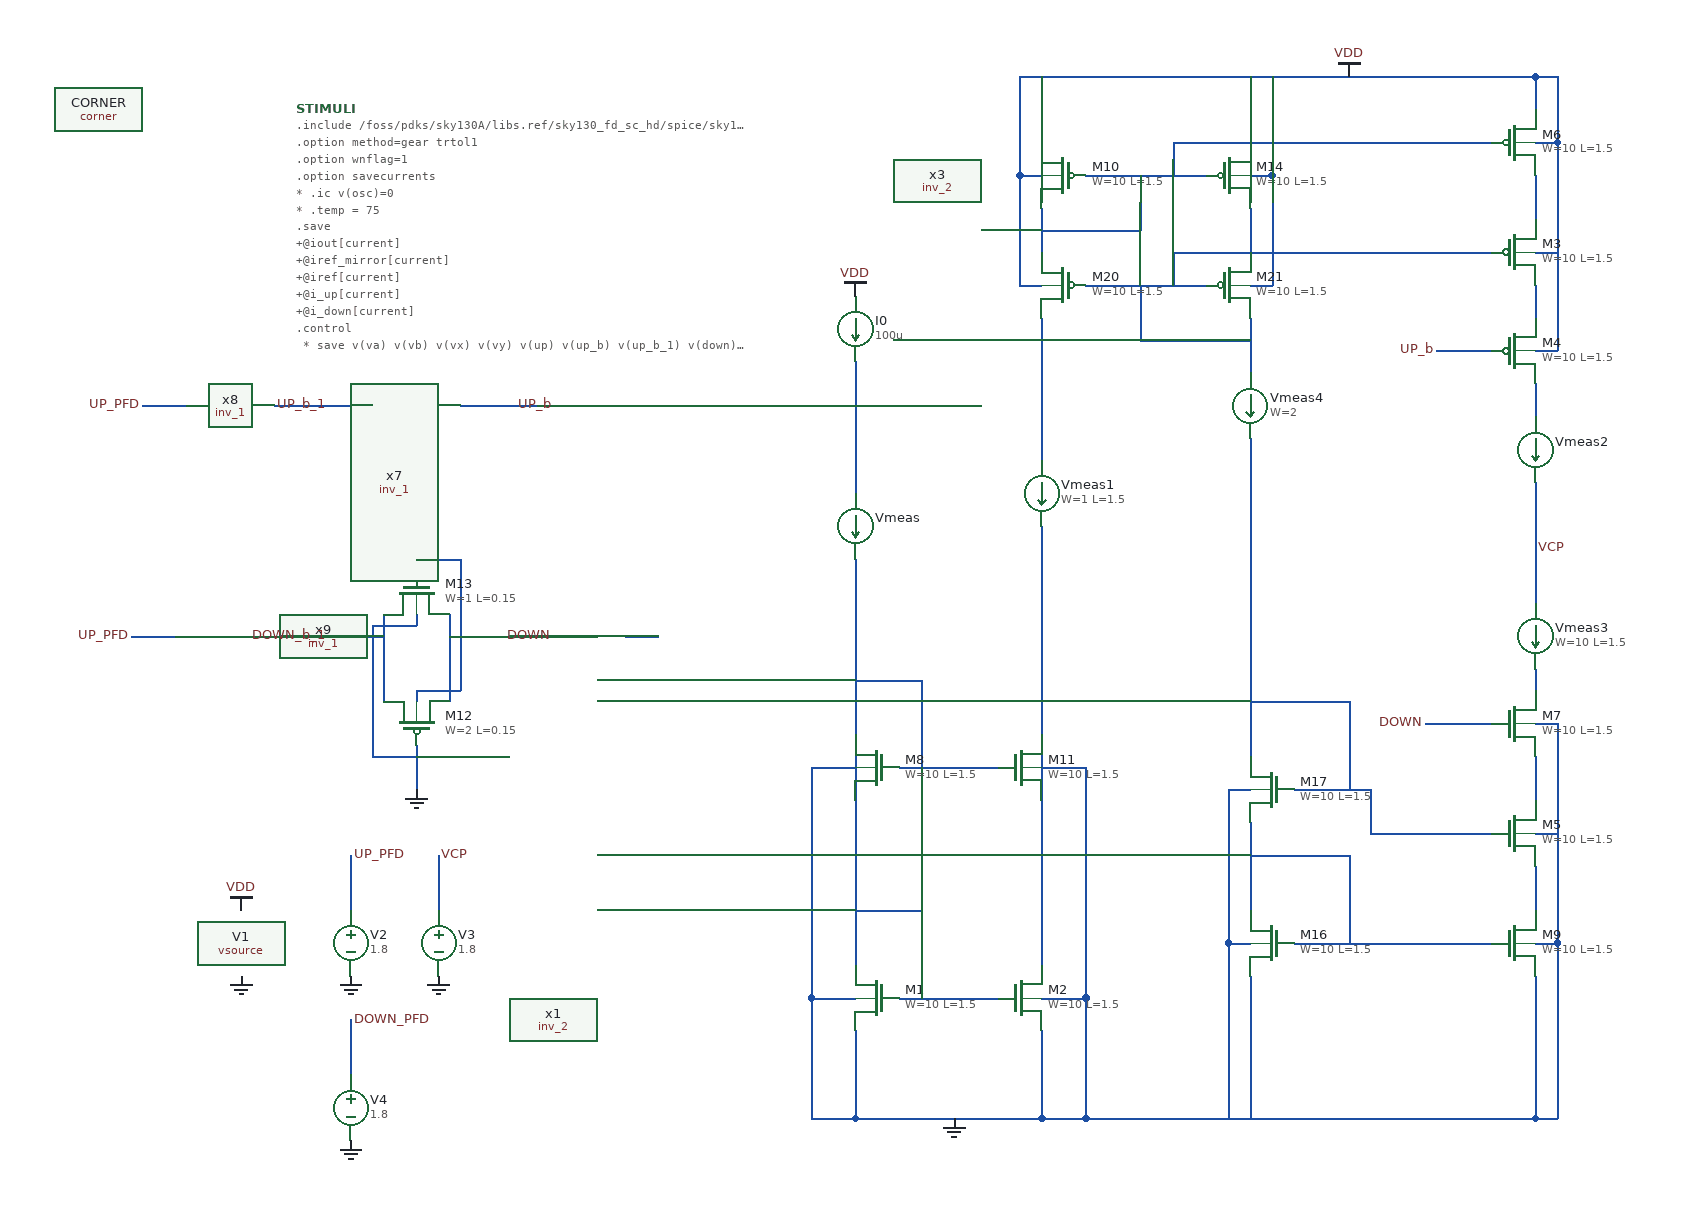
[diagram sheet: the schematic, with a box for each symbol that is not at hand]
v {xschem version=3.4.5 file_version=1.2
}
G {}
K {}
V {}
S {}
E {}
B 2 1530 -1240 2830 -60 {flags=graph
y1=3.6e-120
y2=2e-10
ypos1=0
ypos2=2
divy=5
subdivy=1
unity=1
x1=0
x2=1.8
divx=5
subdivx=1
xlabmag=1.0
ylabmag=1.0


dataset=0
unitx=1
logx=0
logy=0






color="6 5"
node="i(vmeas2)
i(vmeas3)"
linewidth_mult=5}
N 760 -180 850 -180 {
lab=GND}
N 720 -150 720 -70 {
lab=GND}
N 720 -70 890 -70 {
lab=GND}
N 680 -180 720 -180 {
lab=GND}
N 680 -180 680 -70 {
lab=GND}
N 680 -70 720 -70 {
lab=GND}
N 930 -180 930 -70 {
lab=GND}
N 890 -150 890 -70 {
lab=GND}
N 720 -260 780 -260 {
lab=GND}
N 780 -260 780 -180 {
lab=GND}
N 890 -70 930 -70 {
lab=GND}
N 720 -760 720 -710 {
lab=#net1}
N 720 -580 720 -210 {
lab=GND}
N 720 -710 720 -640 {
lab=#net1}
N 1340 -1020 1340 -990 {
lab=VDD}
N 1160 -1020 1340 -1020 {
lab=VDD}
N 1340 -1020 1360 -1020 {
lab=VDD}
N 1360 -1020 1360 -960 {
lab=VDD}
N 1340 -960 1360 -960 {
lab=VDD}
N 930 -70 1240 -70 {
lab=GND}
N 1340 -200 1340 -70 {
lab=GND}
N 1240 -70 1340 -70 {
lab=GND}
N 1340 -230 1360 -230 {
lab=GND}
N 1360 -230 1360 -70 {
lab=GND}
N 1340 -70 1360 -70 {
lab=GND}
N 290 -530 290 -450 {
lab=DOWN_b_1}
N 350 -530 350 -450 {
lab=DOWN}
N 320 -410 320 -370 {
lab=GND}
N 320 -610 320 -570 {
lab=VDD}
N 320 -460 320 -450 {
lab=VDD}
N 320 -460 360 -460 {
lab=VDD}
N 360 -580 360 -460 {
lab=VDD}
N 320 -580 360 -580 {
lab=VDD}
N 320 -530 320 -520 {
lab=GND}
N 280 -520 320 -520 {
lab=GND}
N 280 -520 280 -400 {
lab=GND}
N 280 -400 320 -400 {
lab=GND}
N 190 -720 280 -720 {
lab=UP_b_1}
N 180 -510 290 -510 {
lab=DOWN_b_1}
N 70 -720 110 -720 {
lab=UP_PFD}
N 60 -510 100 -510 {
lab=UP_PFD}
N 260 -310 260 -260 {
lab=UP_PFD}
N 340 -310 340 -260 {
lab=VCP}
N 260 -160 260 -110 {
lab=DOWN_PFD}
N 1340 -400 1340 -360 {
lab=#net2}
N 1340 -300 1340 -260 {
lab=#net3}
N 1340 -830 1340 -800 {
lab=#net4}
N 1340 -930 1340 -880 {
lab=#net5}
N 1340 -770 1360 -770 {
lab=VDD}
N 1360 -960 1360 -770 {
lab=VDD}
N 1340 -860 1360 -860 {
lab=VDD}
N 1340 -430 1360 -430 {
lab=GND}
N 1360 -430 1360 -230 {
lab=GND}
N 1340 -330 1360 -330 {
lab=GND}
N 890 -180 930 -180 {
lab=GND}
N 870 -930 890 -930 {
lab=VDD}
N 870 -1020 870 -930 {
lab=VDD}
N 870 -1020 1160 -1020 {
lab=VDD}
N 930 -930 1040 -930 {
lab=VDD}
N 890 -880 980 -880 {
lab=VDD}
N 980 -930 980 -880 {
lab=VDD}
N 1080 -930 1100 -930 {
lab=VDD}
N 1100 -1020 1100 -930 {
lab=VDD}
N 1060 -230 1080 -230 {
lab=GND}
N 1080 -340 1080 -260 {
lab=#net6}
N 1060 -370 1080 -370 {
lab=GND}
N 1060 -370 1060 -230 {
lab=GND}
N 870 -830 890 -830 {
lab=VDD}
N 930 -830 1040 -830 {
lab=#net7}
N 890 -900 890 -860 {
lab=VDD}
N 1080 -900 1080 -860 {
lab=#net7}
N 980 -830 980 -780 {
lab=#net7}
N 1080 -830 1100 -830 {
lab=VDD}
N 1100 -930 1100 -830 {
lab=VDD}
N 870 -930 870 -830 {
lab=VDD}
N 1250 -770 1300 -770 {
lab=UP_b}
N 1170 -450 1170 -370 {
lab=#net8}
N 1080 -450 1170 -450 {
lab=#net8}
N 1340 -480 1340 -460 {
lab=#net9}
N 1340 -590 1340 -540 {
lab=VCP}
N 1340 -740 1340 -710 {
lab=#net10}
N 890 -610 890 -210 {
lab=GND}
N 890 -800 890 -670 {
lab=#net11}
N 1080 -690 1080 -400 {
lab=#net8}
N 1080 -800 1080 -750 {
lab=#net7}
N 1080 -1020 1080 -960 {
lab=VDD}
N 890 -1020 890 -960 {
lab=VDD}
N 1080 -200 1080 -70 {
lab=GND}
N 1060 -230 1060 -70 {
lab=GND}
N 1170 -310 1170 -230 {
lab=#net6}
N 1080 -310 1170 -310 {
lab=#net6}
N 1120 -230 1300 -230 {
lab=#net6}
N 1120 -370 1190 -370 {
lab=#net8}
N 1190 -370 1190 -330 {
lab=#net8}
N 1190 -330 1300 -330 {
lab=#net8}
N 1340 -650 1340 -590 {
lab=VCP}
N 1010 -960 1300 -960 {
lab=VDD}
N 1010 -960 1010 -930 {
lab=VDD}
N 1010 -860 1300 -860 {
lab=#net7}
N 1010 -860 1010 -830 {
lab=#net7}
N 350 -510 430 -510 {
lab=DOWN}
N 360 -720 430 -720 {
lab=UP_b}
N 510 -720 540 -720 {
lab=#net12}
N 510 -510 540 -510 {
lab=#net13}
N 1240 -430 1300 -430 {
lab=DOWN}
N 760 -390 850 -390 {
lab=GND}
N 680 -390 720 -390 {
lab=GND}
N 720 -470 780 -470 {
lab=GND}
N 780 -470 780 -390 {
lab=GND}
N 890 -390 930 -390 {
lab=GND}
N 930 -390 930 -180 {
lab=GND}
N 680 -390 680 -180 {
lab=GND}
N 980 -780 1080 -780 {
lab=#net7}
C {sky130_fd_pr/nfet_01v8.sym} 740 -180 0 1 {name=M1
L=1.5
W=10
nf=1 
mult=12
ad="'int((nf+1)/2) * W/nf * 0.29'" 
pd="'2*int((nf+1)/2) * (W/nf + 0.29)'"
as="'int((nf+2)/2) * W/nf * 0.29'" 
ps="'2*int((nf+2)/2) * (W/nf + 0.29)'"
nrd="'0.29 / W'" nrs="'0.29 / W'"
sa=0 sb=0 sd=0
model=nfet_01v8
spiceprefix=X
}
C {sky130_fd_pr/nfet_01v8.sym} 870 -180 0 0 {name=M2
L=1.5
W=10
nf=1 
mult=12
ad="'int((nf+1)/2) * W/nf * 0.29'" 
pd="'2*int((nf+1)/2) * (W/nf + 0.29)'"
as="'int((nf+2)/2) * W/nf * 0.29'" 
ps="'2*int((nf+2)/2) * (W/nf + 0.29)'"
nrd="'0.29 / W'" nrs="'0.29 / W'"
sa=0 sb=0 sd=0
model=nfet_01v8
spiceprefix=X
}
C {devices/gnd.sym} 810 -70 0 0 {name=l14 lab=GND}
C {sky130_fd_pr/corner.sym} 30 -990 0 0 {name=CORNER only_toplevel=false corner=tt}
C {devices/code.sym} 210 -991.25 0 0 {name=STIMULI only_toplevel=false value="

.include /foss/pdks/sky130A/libs.ref/sky130_fd_sc_hd/spice/sky130_fd_sc_hd.spice

.option method=gear trtol1
.option wnflag=1
.option savecurrents

* .ic v(osc)=0
* .temp = 75

.save 
+@iout[current]
+@iref_mirror[current]
+@iref[current]
+@i_up[current]
+@i_down[current]


.control
  * save v(va) v(vb) v(vx) v(vy) v(up) v(up_b) v(up_b_1) v(down) v(down_b) v(down_b_1) v(vref) v(vcp)
  save all
  * tran 0.1ns 10us
  dc V3 0 1.8 0.01 V2 0 1.8 1.8 
  remzerovec
  write charge_pump_DC3.raw
  * wrdata /foss/designs/my_design/projects/pll/pfd/xschem_ngspice/charge_pump2_QA.txt v(osc)
  set appendwrite

.endc




"}
C {devices/vsource.sym} 160 -230 0 0 {name=V1 value=1.8 savecurrent=false}
C {devices/gnd.sym} 160 -200 0 0 {name=l2 lab=GND}
C {devices/vdd.sym} 160 -260 0 1 {name=l3 lab=VDD}
C {devices/isource.sym} 720 -790 0 0 {name=I0 value=100u}
C {devices/vdd.sym} 720 -820 0 1 {name=l5 lab=VDD}
C {devices/ammeter.sym} 720 -610 0 0 {name=Vmeas savecurrent=true spice_ignore=0}
C {sky130_fd_pr/pfet_01v8.sym} 1320 -960 0 0 {name=M6
L=1.5
W=10
nf=1
mult=30
ad="'int((nf+1)/2) * W/nf * 0.29'" 
pd="'2*int((nf+1)/2) * (W/nf + 0.29)'"
as="'int((nf+2)/2) * W/nf * 0.29'" 
ps="'2*int((nf+2)/2) * (W/nf + 0.29)'"
nrd="'0.29 / W'" nrs="'0.29 / W'"
sa=0 sb=0 sd=0
model=pfet_01v8
spiceprefix=X
}
C {devices/ammeter.sym} 1340 -680 0 0 {name=Vmeas2 savecurrent=true spice_ignore=0
nf=2}
C {devices/ammeter.sym} 1340 -510 0 0 {name=Vmeas3 savecurrent=true spice_ignore=0
L=1.5
W=10
nf=1
mult=12}
C {sky130_fd_pr/nfet_01v8.sym} 1320 -230 0 0 {name=M9
L=1.5
W=10
nf=1 
mult=12
ad="'int((nf+1)/2) * W/nf * 0.29'" 
pd="'2*int((nf+1)/2) * (W/nf + 0.29)'"
as="'int((nf+2)/2) * W/nf * 0.29'" 
ps="'2*int((nf+2)/2) * (W/nf + 0.29)'"
nrd="'0.29 / W'" nrs="'0.29 / W'"
sa=0 sb=0 sd=0
model=nfet_01v8
spiceprefix=X
}
C {sky130_fd_pr/pfet_01v8.sym} 320 -430 3 0 {name=M12
L=0.15
W=2
nf=2
mult=1
ad="'int((nf+1)/2) * W/nf * 0.29'" 
pd="'2*int((nf+1)/2) * (W/nf + 0.29)'"
as="'int((nf+2)/2) * W/nf * 0.29'" 
ps="'2*int((nf+2)/2) * (W/nf + 0.29)'"
nrd="'0.29 / W'" nrs="'0.29 / W'"
sa=0 sb=0 sd=0
model=pfet_01v8
spiceprefix=X
}
C {sky130_fd_pr/nfet_01v8.sym} 320 -550 1 0 {name=M13
L=0.15
W=1
nf=1 
mult=1
ad="'int((nf+1)/2) * W/nf * 0.29'" 
pd="'2*int((nf+1)/2) * (W/nf + 0.29)'"
as="'int((nf+2)/2) * W/nf * 0.29'" 
ps="'2*int((nf+2)/2) * (W/nf + 0.29)'"
nrd="'0.29 / W'" nrs="'0.29 / W'"
sa=0 sb=0 sd=0
model=nfet_01v8
spiceprefix=X
}
C {devices/vdd.sym} 320 -610 0 0 {name=l11 lab=VDD}
C {devices/gnd.sym} 320 -370 0 0 {name=l12 lab=GND}
C {sky130_stdcells/inv_1.sym} 320 -720 0 0 {name=x7 VGND=GND VNB=GND VPB=VDD VPWR=VDD prefix=sky130_fd_sc_hd__ }
C {sky130_stdcells/inv_1.sym} 150 -720 0 0 {name=x8 VGND=GND VNB=GND VPB=VDD VPWR=VDD prefix=sky130_fd_sc_hd__ }
C {sky130_stdcells/inv_1.sym} 140 -510 0 0 {name=x9 VGND=GND VNB=GND VPB=VDD VPWR=VDD prefix=sky130_fd_sc_hd__ }
C {devices/lab_wire.sym} 70 -720 0 0 {name=p2 sig_type=std_logic lab=UP_PFD}
C {devices/lab_wire.sym} 240 -720 0 0 {name=p15 sig_type=std_logic lab=UP_b_1}
C {devices/lab_wire.sym} 240 -510 2 1 {name=p16 sig_type=std_logic lab=DOWN_b_1}
C {devices/vsource.sym} 260 -230 0 0 {name=V2 value=1.8 savecurrent=false
* "pwl()"}
C {devices/gnd.sym} 260 -200 0 0 {name=l1 lab=GND}
C {devices/lab_wire.sym} 260 -310 0 1 {name=p10 sig_type=std_logic lab=UP_PFD}
C {devices/vsource.sym} 340 -230 0 0 {name=V3 value=1.8 savecurrent=false}
C {devices/gnd.sym} 340 -200 0 0 {name=l4 lab=GND}
C {devices/lab_wire.sym} 340 -310 0 1 {name=p12 sig_type=std_logic lab=VCP}
C {devices/vsource.sym} 260 -80 0 0 {name=V4 value=1.8 savecurrent=false
* "pwl()"}
C {devices/gnd.sym} 260 -50 0 0 {name=l8 lab=GND}
C {devices/lab_wire.sym} 260 -160 0 1 {name=p18 sig_type=std_logic lab=DOWN_PFD}
C {devices/lab_wire.sym} 1340 -590 0 1 {name=p9 sig_type=std_logic lab=VCP}
C {sky130_fd_pr/pfet_01v8.sym} 1320 -860 0 0 {name=M3
L=1.5
W=10
nf=1
mult=30
ad="'int((nf+1)/2) * W/nf * 0.29'" 
pd="'2*int((nf+1)/2) * (W/nf + 0.29)'"
as="'int((nf+2)/2) * W/nf * 0.29'" 
ps="'2*int((nf+2)/2) * (W/nf + 0.29)'"
nrd="'0.29 / W'" nrs="'0.29 / W'"
sa=0 sb=0 sd=0
model=pfet_01v8
spiceprefix=X
}
C {sky130_fd_pr/pfet_01v8.sym} 1320 -770 0 0 {name=M4
L=1.5
W=10
nf=1
mult=30
ad="'int((nf+1)/2) * W/nf * 0.29'" 
pd="'2*int((nf+1)/2) * (W/nf + 0.29)'"
as="'int((nf+2)/2) * W/nf * 0.29'" 
ps="'2*int((nf+2)/2) * (W/nf + 0.29)'"
nrd="'0.29 / W'" nrs="'0.29 / W'"
sa=0 sb=0 sd=0
model=pfet_01v8
spiceprefix=X
}
C {sky130_fd_pr/nfet_01v8.sym} 1320 -330 0 0 {name=M5
L=1.5
W=10
nf=1 
mult=12
ad="'int((nf+1)/2) * W/nf * 0.29'" 
pd="'2*int((nf+1)/2) * (W/nf + 0.29)'"
as="'int((nf+2)/2) * W/nf * 0.29'" 
ps="'2*int((nf+2)/2) * (W/nf + 0.29)'"
nrd="'0.29 / W'" nrs="'0.29 / W'"
sa=0 sb=0 sd=0
model=nfet_01v8
spiceprefix=X
}
C {sky130_fd_pr/nfet_01v8.sym} 1320 -430 0 0 {name=M7
L=1.5
W=10
nf=1 
mult=12
ad="'int((nf+1)/2) * W/nf * 0.29'" 
pd="'2*int((nf+1)/2) * (W/nf + 0.29)'"
as="'int((nf+2)/2) * W/nf * 0.29'" 
ps="'2*int((nf+2)/2) * (W/nf + 0.29)'"
nrd="'0.29 / W'" nrs="'0.29 / W'"
sa=0 sb=0 sd=0
model=nfet_01v8
spiceprefix=X
}
C {sky130_fd_pr/pfet_01v8.sym} 910 -930 0 1 {name=M10
L=1.5
W=10
nf=1
mult=30
ad="'int((nf+1)/2) * W/nf * 0.29'" 
pd="'2*int((nf+1)/2) * (W/nf + 0.29)'"
as="'int((nf+2)/2) * W/nf * 0.29'" 
ps="'2*int((nf+2)/2) * (W/nf + 0.29)'"
nrd="'0.29 / W'" nrs="'0.29 / W'"
sa=0 sb=0 sd=0
model=pfet_01v8
spiceprefix=X
}
C {sky130_fd_pr/pfet_01v8.sym} 1060 -930 0 0 {name=M14
L=1.5
W=10
nf=1
mult=30
ad="'int((nf+1)/2) * W/nf * 0.29'" 
pd="'2*int((nf+1)/2) * (W/nf + 0.29)'"
as="'int((nf+2)/2) * W/nf * 0.29'" 
ps="'2*int((nf+2)/2) * (W/nf + 0.29)'"
nrd="'0.29 / W'" nrs="'0.29 / W'"
sa=0 sb=0 sd=0
model=pfet_01v8
spiceprefix=X
}
C {sky130_fd_pr/nfet_01v8.sym} 1100 -230 0 1 {name=M16
L=1.5
W=10
nf=1 
mult=12
ad="'int((nf+1)/2) * W/nf * 0.29'" 
pd="'2*int((nf+1)/2) * (W/nf + 0.29)'"
as="'int((nf+2)/2) * W/nf * 0.29'" 
ps="'2*int((nf+2)/2) * (W/nf + 0.29)'"
nrd="'0.29 / W'" nrs="'0.29 / W'"
sa=0 sb=0 sd=0
model=nfet_01v8
spiceprefix=X
}
C {sky130_fd_pr/nfet_01v8.sym} 1100 -370 0 1 {name=M17
L=1.5
W=10
nf=1 
mult=12
ad="'int((nf+1)/2) * W/nf * 0.29'" 
pd="'2*int((nf+1)/2) * (W/nf + 0.29)'"
as="'int((nf+2)/2) * W/nf * 0.29'" 
ps="'2*int((nf+2)/2) * (W/nf + 0.29)'"
nrd="'0.29 / W'" nrs="'0.29 / W'"
sa=0 sb=0 sd=0
model=nfet_01v8
spiceprefix=X
}
C {sky130_fd_pr/pfet_01v8.sym} 910 -830 0 1 {name=M20
L=1.5
W=10
nf=1
mult=30
ad="'int((nf+1)/2) * W/nf * 0.29'" 
pd="'2*int((nf+1)/2) * (W/nf + 0.29)'"
as="'int((nf+2)/2) * W/nf * 0.29'" 
ps="'2*int((nf+2)/2) * (W/nf + 0.29)'"
nrd="'0.29 / W'" nrs="'0.29 / W'"
sa=0 sb=0 sd=0
model=pfet_01v8
spiceprefix=X
}
C {sky130_fd_pr/pfet_01v8.sym} 1060 -830 0 0 {name=M21
L=1.5
W=10
nf=1
mult=30
ad="'int((nf+1)/2) * W/nf * 0.29'" 
pd="'2*int((nf+1)/2) * (W/nf + 0.29)'"
as="'int((nf+2)/2) * W/nf * 0.29'" 
ps="'2*int((nf+2)/2) * (W/nf + 0.29)'"
nrd="'0.29 / W'" nrs="'0.29 / W'"
sa=0 sb=0 sd=0
model=pfet_01v8
spiceprefix=X
}
C {devices/vdd.sym} 1170 -1020 0 1 {name=l6 lab=VDD}
C {devices/ammeter.sym} 890 -640 0 0 {name=Vmeas1 savecurrent=true spice_ignore=0
L=1.5
W=1
nf=1}
C {devices/ammeter.sym} 1080 -720 0 0 {name=Vmeas4 savecurrent=true spice_ignore=0
W=2
nf=2}
C {sky130_stdcells/inv_2.sym} 470 -720 0 0 {name=x3 VGND=GND VNB=GND VPB=VDD VPWR=VDD prefix=sky130_fd_sc_hd__ }
C {sky130_stdcells/inv_2.sym} 470 -510 0 0 {name=x1 VGND=GND VNB=GND VPB=VDD VPWR=VDD prefix=sky130_fd_sc_hd__ }
C {devices/lab_wire.sym} 410 -720 0 1 {name=p1 sig_type=std_logic lab=UP_b}
C {devices/lab_wire.sym} 400 -510 0 1 {name=p3 sig_type=std_logic lab=DOWN}
C {devices/lab_wire.sym} 60 -510 0 0 {name=p4 sig_type=std_logic lab=UP_PFD}
C {devices/lab_wire.sym} 1250 -770 0 0 {name=p5 sig_type=std_logic lab=UP_b
L=1.5
W=10
nf=1
mult=30}
C {devices/lab_wire.sym} 1240 -430 2 1 {name=p6 sig_type=std_logic lab=DOWN
W=10
nf=1
L=1.5
mult=12}
C {sky130_fd_pr/nfet_01v8.sym} 740 -390 0 1 {name=M8
L=1.5
W=10
nf=1 
mult=12
ad="'int((nf+1)/2) * W/nf * 0.29'" 
pd="'2*int((nf+1)/2) * (W/nf + 0.29)'"
as="'int((nf+2)/2) * W/nf * 0.29'" 
ps="'2*int((nf+2)/2) * (W/nf + 0.29)'"
nrd="'0.29 / W'" nrs="'0.29 / W'"
sa=0 sb=0 sd=0
model=nfet_01v8
spiceprefix=X
}
C {sky130_fd_pr/nfet_01v8.sym} 870 -390 0 0 {name=M11
L=1.5
W=10
nf=1 
mult=12
ad="'int((nf+1)/2) * W/nf * 0.29'" 
pd="'2*int((nf+1)/2) * (W/nf + 0.29)'"
as="'int((nf+2)/2) * W/nf * 0.29'" 
ps="'2*int((nf+2)/2) * (W/nf + 0.29)'"
nrd="'0.29 / W'" nrs="'0.29 / W'"
sa=0 sb=0 sd=0
model=nfet_01v8
spiceprefix=X
}
